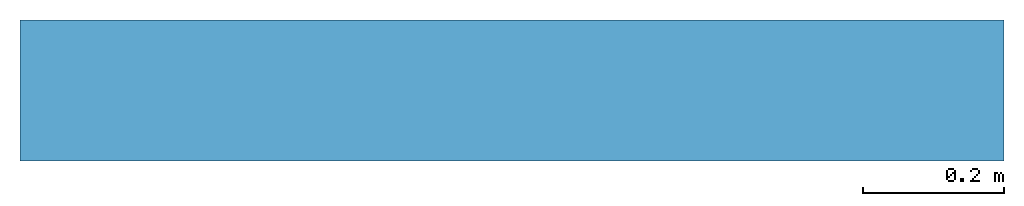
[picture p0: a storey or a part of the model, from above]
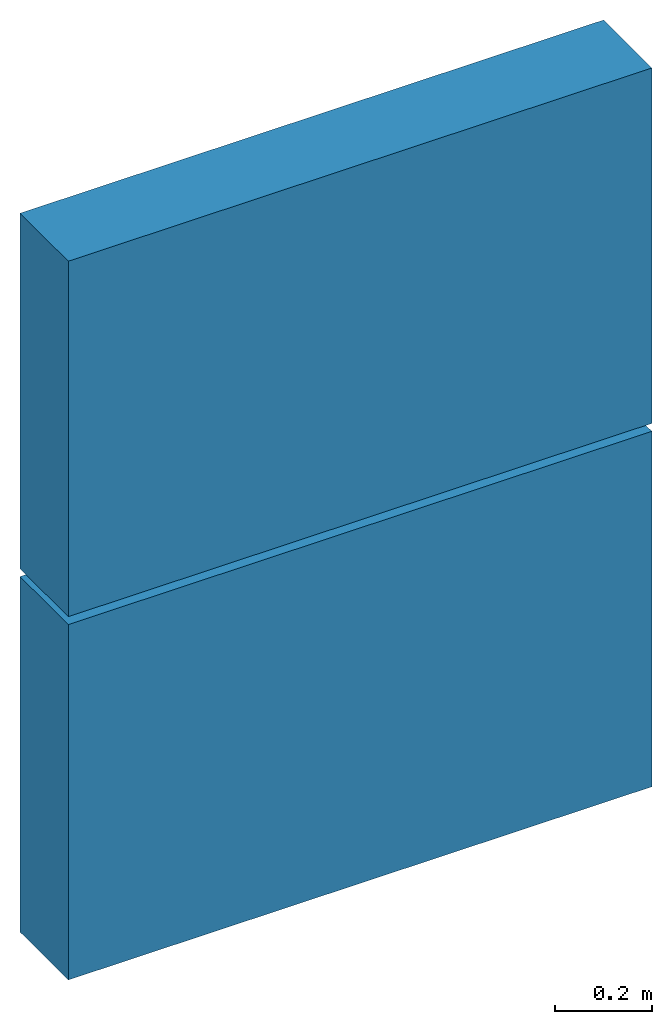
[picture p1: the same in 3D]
Properties of the parts of a building model (IFC2X3), part 1 of 2

# File
Description: ViewDefinition [CoordinationView_V2.0]
File name: Project Number
Time: 2020-09-23T15:33:14
Written by: The EXPRESS Data Manager Version 5.02.0100.07 : 28 Aug 2013
Made in: 21.0.0.383 - Exporter 21.0.0.383 - Alternate UI 21.0.0.383
Comment: STEP Physical File produced by: The EXPRESS Data Manager Version 5.02.0100.07 : 28 Aug 2013 * Module: EDMstepFileFactory/EDMstandAlone * Creation date: Wed Sep 23 15:33:14 2020 * Host: DESKTOP-DG8BND5 * Database: C:\Users\X\AppData\Local\Temp\6b4c7af7-08d6-41d8-b2e5-88945e1ad714\b9ea3a23-58ec-455c-9557-a9c1af2dff10\ifc * Database version: 5507 * Database creation date: Wed Sep 23 15:31:38 2020 * Schema: IFC2X3 * Model: DataRepository.ifc * Model creation date: Wed Sep 23 15:31:39 2020 * Header model: DataRepository.ifc_HeaderModel * Header model creation date: Wed Sep 23 15:31:39 2020 * EDMuser: sdai-user * EDMgroup: sdai-group * License ID and type: 5605 : Permanent license. Expiry date: * EDMstepFileFactory options: 020000

# IfcProject, Project Number
LongName: Project Name; Phase: Project Status

# IfcSite, Default
RefLatitude: 48, 41, 46, 352233; RefLongitude: 6, 11, 34, 519615; RefElevation: 0 mm
Pset_ProductRequirements - Category: Project Information
Other - Category: Project Information; Client Name: Owner; Project Address: Enter address here; Project Issue Date: Issue Date; Project Name: Project Name; Project Number: Project Number; Project Status: Project Status

# IfcBuilding
Pset_BuildingCommon - NumberOfStoreys: 5
Pset_ProductRequirements - Category: Project Information
Other - Category: Project Information; Client Name: Owner; Project Address: Enter address here; Project Issue Date: Issue Date; Project Name: Project Name; Project Number: Project Number; Project Status: Project Status

# IfcBuildingStorey: Level:Circle Head - Project Datum (5)
Other(Type) - Category: Levels; Family Name: Level
Identity Data(Type) - Type Name: Circle Head - Project Datum
Graphics(Type) - Color: 0; Line Pattern: Centre; Line Weight: 1; Symbol: Anno_Level_Head_Circle: Standard; Symbol at End 1 Default: yes; Symbol at End 2 Default: no
Constraints(Type) - Elevation Base: Project Base Point
Pset_ProductRequirements - Category: Levels
Dimensions - Computation Height: 0 mm
Identity Data - Building Story: yes
Other - Category: Levels; Family: Level: Circle Head - Project Datum; Family and Type: Level: Circle Head - Project Datum; Type: Level: Circle Head - Project Datum; Type Id: Level: Circle Head - Project Datum
Name | LongName = Pset_AirSideSystemInformation, Name = Pset_ProductRequirements, Name = Identity Data, Name | Elevation (mm) = Constraints, Elevation (mm) | Structural
R-1 | R-1 | -3500 | yes
RDC | RDC | 0 | no
R+1 | R+1 | 3660 | no
R+2 | R+2 | 7320 | no
TOITURE | TOITURE | 10840 | yes

# IfcBeam: M_Concrete-Rectangular Beam:200x300 mm, M_Concrete-Rectangular Beam:200x300 mm:497822
In: R-1
Type - Dimensions - b: 200 mm; h: 300 mm
Type - Identity Data - OmniClass Number: 23.25.30.11.14.14; OmniClass Title: Beams; Type Name: 200x300 mm
Type - Other - Category: Structural Framing; Family Name: M_Concrete-Rectangular Beam
Type - Structural - Section Shape: 0
Type - Pset_BeamCommon - IsExternal: no; LoadBearing: yes; Reference: 200x300 mm
Type - Pset_ProductRequirements - Category: Structural Framing
Type - Pset_QuantityTakeOff - Reference: 200x300 mm
Type - Pset_ReinforcementBarPitchOfBeam - Reference: 200x300 mm
Material: Concrete, Cast-in-Place gray
Pset_BeamCommon - Slope: 0 deg; Span: 1739.96 mm
Pset_QuantityTakeOff - sets with these values: 2
Constraints - Cross-Section Rotation: 0 deg; End Level Offset: 2330 mm; Reference Level: Level: R-1; Reference Level Elevation: -3500 mm; Start Level Offset: 2330 mm
Dimensions - Elevation at Bottom: -1470 mm; Elevation at Top: -1170 mm; Length: 1739.96 mm; Volume: 0.0989977 m3
Geometric Position - Join Status: Both joins enabled; y Justification: Origin; y Offset Value: 0 mm; yz Justification: Uniform; z Justification: Top; z Offset Value: 0 mm
Materials and Finishes - Structural Material: Concrete, Cast-in-Place gray
Other - Family: M_Concrete-Rectangular Beam: 200x300 mm; Family and Type: M_Concrete-Rectangular Beam: 200x300 mm; Type: M_Concrete-Rectangular Beam: 200x300 mm; Type Id: M_Concrete-Rectangular Beam: 200x300 mm
Phasing - Phase Created: New Construction
Structural - Enable Analytical Model: yes; Rebar Cover - Bottom Face: Rebar Cover Settings: Rebar Cover 1; Rebar Cover - Other Faces: Rebar Cover Settings: Rebar Cover 1; Rebar Cover - Top Face: Rebar Cover Settings: Rebar Cover 1; Cut Length: 1649.96 mm; Structural Usage: Secondary

# IfcBeam: NBS_AndertonConcreteProductsLtd_PrcstConcPnls_BallastBoard300:PPT TYPE4 (42)
Type - Constraints - Default Elevation: 0 mm
Type - Data - EdgeDetails: Plain; EnvironmentalProductDeclaration: n/a; Weight: 60 kg
Type - Dimensions - Height: 898.3 mm; Length: 8120 mm; Width: 200 mm
Type - General - Author: NBS; BIMObjectName: NBS_AndertonConcreteProductsLtd_PrecastConcretePanels_BallastBoard300; ManufacturerName: Anderton Concrete Products Ltd; NBSDescription: Precast concrete paels; Revision: n/a; Uniclass2015Code: Pr_20_93_71_17; Uniclass2015Title: Concrete panels; Uniclass2015Version: Products v1.5; Version: 4
Type - Identity Data - Type Name: PPT TYPE4
Type - Materials and Finishes - PanelMaterial: Concrete, Precast Smooth, Light Grey
Type - Other - Category: Generic Models; AccessibilityPerformance: n/a; AssetType: Fixed; CodePerformance: n/a; Color: n/a; Constituents: n/a; DurationUnit: year; ExpectedLife: n/a; Family Name: NBS_AndertonConcreteProductsLtd_PrcstConcPnls_BallastBoard300; Features: Quick and easy to install, contains steel reinforcement, Network Rail approved; Finish: n/a; Grade: n/a; Material: Concrete; ModelNumber: n/a; ModelReference: Ballast Board; Name: PrecastConcretePanels_BallastBoard300_AndertonConcreteProductsLtd; NominalHeight: 2910 mm; NominalLength: 10337 mm; NominalWidth: 200 mm; ReplacementCost: n/a; Shape: Rectangular; Size: 1830 x 300 x 50 mm; SustainabilityPerformance: n/a; WarrantyDescription: n/a; WarrantyDurationLabor: n/a; WarrantyDurationParts: n/a; WarrantyDurationUnit: year; WarrantyGuarantorLabor: n/a; WarrantyGuarantorParts: n/a
Type - Pset_BeamCommon - LoadBearing: yes; Reference: n/a; Slope: 0 deg; IsExternal: yes; Span: 1830 mm; FireRating: n/a
Type - Pset_ConcreteElementGeneral - EnvironmentalClass: n/a; FireRating: n/a; LifeCycleEnvironmentalLoad: n/a; DimensionalAccuracyClass: n/a; ConstructionToleranceClass: n/a; ConstructionType: n/a
Type - Pset_ElementShading - Color: n/a
Type - Pset_ManufacturerTypeInformation - ModelReference: Ballast Board
Type - Pset_ProductRequirements - Name: PrecastConcretePanels_BallastBoard300_AndertonConcreteProductsLtd; Category: Generic Models
Type - Pset_QuantityTakeOff - Reference: n/a
Type - Pset_ReinforcementBarPitchOfBeam - Reference: n/a
Material: Concrete, Precast Smooth, Light Grey
Pset_ManufacturerOccurrence - BarCode: n/a; SerialNumber: n/a
Pset_PrecastConcreteElementGeneral - SerialNumber: n/a
Pset_QuantityTakeOff - sets with these values: 2
Constraints - Moves With Nearby Elements: no
Dimensions - Area: 9.09786 m2; Volume: 1.45884 m3
Other - AssetIdentifier: n/a; BarCode: n/a; Family: NBS_AndertonConcreteProductsLtd_PrcstConcPnls_BallastBoard300: PPT TYPE4; Family and Type: NBS_AndertonConcreteProductsLtd_PrcstConcPnls_BallastBoard300: PPT TYPE4; InstallationDate: 1900-12-31T23:59:59; SerialNumber: n/a; TagNumber: n/a; Type: NBS_AndertonConcreteProductsLtd_PrcstConcPnls_BallastBoard300: PPT TYPE4; Type Id: NBS_AndertonConcreteProductsLtd_PrcstConcPnls_BallastBoard300: PPT TYPE4; WarrantyStartDate: 1900-12-31T23:59:59
Structural - Rebar Cover: Rebar Cover Settings: Rebar Cover 1
Name (NBS_AndertonConcreteProductsLtd_PrcstConcPnls_BallastBoard300:PPT TYPE4:...) | In | Level | Elevation from Level (mm) = Offset from Host (mm) | Host | Comments | Phase Created
424100 | RDC | Level: RDC | 2010 | Level : RDC | ThisIsNew | New Construction
424610 | RDC | Level: RDC | 1091.7 | Level : RDC | ThisIsNew | New Construction
424641 | RDC | Level: RDC | 173.4 | Level : RDC | ThisIsNew | New Construction
424680 | RDC | Level: RDC | 2928.3 | Level : RDC | ThisIsNew | New Construction
424690 | R+1 | Level: R+1 | 186.6 | Level : R+1 | ThisIsNew | New Construction
424729 | R+1 | Level: R+1 | 1104.9 | Level : R+1 | ThisIsNew | New Construction
424743 | R+1 | Level: R+1 | 2023.2 | Level : R+1 | ThisIsNew | New Construction
424763 | R+1 | Level: R+1 | 2941.5 | Level : R+1 | ThisIsNew | New Construction
424773 | R+2 | Level: R+2 | 199.8 | Level : R+2 | ThisIsNew | New Construction
430433 | RDC | Level: RDC | 2928.3 | Level : RDC | ThisIsExisting | Existing
430434 | R+1 | Level: R+1 | 186.6 | Level : R+1 | ThisIsExisting | Existing
430435 | R+1 | Level: R+1 | 1104.9 | Level : R+1 | ThisIsExisting | Existing
430436 | R+1 | Level: R+1 | 2023.2 | Level : R+1 | ThisIsExisting | Existing
430437 | R+1 | Level: R+1 | 2941.5 | Level : R+1 | ThisIsExisting | Existing
430438 | R+2 | Level: R+2 | 199.8 | Level : R+2 | ThisIsExisting | Existing
585489 | R+2 | Level: R+2 | 1118.1 | Level : R+2 | ThisIsExisting | Existing
585513 | R+2 | Level: R+2 | 2036.4 | Level : R+2 | ThisIsExisting | Existing
585540 | R+2 | Level: R+2 | 2954.7 | Level : R+2 | ThisIsExisting | Existing
585692 | RDC | Level: RDC | 2010 | Level : RDC | ThisIsExisting | Existing
585693 | RDC | Level: RDC | 1091.7 | Level : RDC | ThisIsExisting | Existing
585694 | RDC | Level: RDC | 173.4 | Level : RDC | ThisIsExisting | Existing
585695 | RDC | Level: RDC | 2928.3 | Level : RDC | ThisIsExisting | Existing
585696 | R+1 | Level: R+1 | 186.6 | Level : R+1 | ThisIsExisting | Existing
585697 | R+1 | Level: R+1 | 1104.9 | Level : R+1 | ThisIsExisting | Existing
585698 | R+1 | Level: R+1 | 2023.2 | Level : R+1 | ThisIsExisting | Existing
585699 | R+1 | Level: R+1 | 2941.5 | Level : R+1 | ThisIsExisting | Existing
585700 | R+2 | Level: R+2 | 199.8 | Level : R+2 | ThisIsExisting | Existing
585701 | RDC | Level: RDC | 2928.3 | Level : RDC | ThisIsExisting | Existing
585702 | R+1 | Level: R+1 | 186.6 | Level : R+1 | ThisIsExisting | Existing
585703 | R+1 | Level: R+1 | 1104.9 | Level : R+1 | ThisIsExisting | Existing
585704 | R+1 | Level: R+1 | 2023.2 | Level : R+1 | ThisIsExisting | Existing
585705 | R+1 | Level: R+1 | 2941.5 | Level : R+1 | ThisIsExisting | Existing
585706 | R+2 | Level: R+2 | 199.8 | Level : R+2 | ThisIsExisting | Existing
585707 | R+2 | Level: R+2 | 1118.1 | Level : R+2 | ThisIsExisting | Existing
585708 | R+2 | Level: R+2 | 2036.4 | Level : R+2 | ThisIsExisting | Existing
585709 | R+2 | Level: R+2 | 2954.7 | Level : R+2 | ThisIsExisting | Existing
585859 | R+2 | Level: R+2 | 1118.1 | Level : R+2 | ThisIsExisting | Existing
585870 | R+2 | Level: R+2 | 2036.4 | Level : R+2 | ThisIsExisting | Existing
586358 | R+2 | Level: R+2 | 1118.1 | Level : R+2 | ThisIsNew | New Construction
586370 | R+2 | Level: R+2 | 2036.4 | Level : R+2 | ThisIsNew | New Construction
586384 | R+2 | Level: R+2 | 2954.7 | Level : R+2 | ThisIsNew | New Construction
586434 | R+2 | Level: R+2 | 2954.7 | Level : R+2 | ThisIsExisting | Existing

# IfcBeam: NBS_AndertonConcreteProductsLtd_PrcstConcPnls_BallastBoard300:PPT TYPE5 (42)
Type - Constraints - Default Elevation: 0 mm
Type - Data - EdgeDetails: Plain; EnvironmentalProductDeclaration: n/a; Weight: 60 kg
Type - Dimensions - Height: 898.3 mm; Length: 1525 mm; Width: 200 mm
Type - General - Author: NBS; BIMObjectName: NBS_AndertonConcreteProductsLtd_PrecastConcretePanels_BallastBoard300; ManufacturerName: Anderton Concrete Products Ltd; NBSDescription: Precast concrete paels; Revision: n/a; Uniclass2015Code: Pr_20_93_71_17; Uniclass2015Title: Concrete panels; Uniclass2015Version: Products v1.5; Version: 4
Type - Identity Data - Type Name: PPT TYPE5
Type - Materials and Finishes - PanelMaterial: Concrete, Precast Smooth, Light Grey
Type - Other - Category: Generic Models; AccessibilityPerformance: n/a; AssetType: Fixed; CodePerformance: n/a; Color: n/a; Constituents: n/a; DurationUnit: year; ExpectedLife: n/a; Family Name: NBS_AndertonConcreteProductsLtd_PrcstConcPnls_BallastBoard300; Features: Quick and easy to install, contains steel reinforcement, Network Rail approved; Finish: n/a; Grade: n/a; Material: Concrete; ModelNumber: n/a; ModelReference: Ballast Board; Name: PrecastConcretePanels_BallastBoard300_AndertonConcreteProductsLtd; NominalHeight: 2910 mm; NominalLength: 10337 mm; NominalWidth: 200 mm; ReplacementCost: n/a; Shape: Rectangular; Size: 1830 x 300 x 50 mm; SustainabilityPerformance: n/a; WarrantyDescription: n/a; WarrantyDurationLabor: n/a; WarrantyDurationParts: n/a; WarrantyDurationUnit: year; WarrantyGuarantorLabor: n/a; WarrantyGuarantorParts: n/a
Type - Pset_BeamCommon - LoadBearing: yes; Reference: n/a; Slope: 0 deg; IsExternal: yes; Span: 1830 mm; FireRating: n/a
Type - Pset_ConcreteElementGeneral - EnvironmentalClass: n/a; FireRating: n/a; LifeCycleEnvironmentalLoad: n/a; DimensionalAccuracyClass: n/a; ConstructionToleranceClass: n/a; ConstructionType: n/a
Type - Pset_ElementShading - Color: n/a
Type - Pset_ManufacturerTypeInformation - ModelReference: Ballast Board
Type - Pset_ProductRequirements - Name: PrecastConcretePanels_BallastBoard300_AndertonConcreteProductsLtd; Category: Generic Models
Type - Pset_QuantityTakeOff - Reference: n/a
Type - Pset_ReinforcementBarPitchOfBeam - Reference: n/a
Material: Concrete, Precast Smooth, Light Grey
Pset_ManufacturerOccurrence - BarCode: n/a; SerialNumber: n/a
Pset_PrecastConcreteElementGeneral - SerialNumber: n/a
Pset_QuantityTakeOff - sets with these values: 2
Constraints - Moves With Nearby Elements: no
Dimensions - Area: 1.85457 m2; Volume: 0.273982 m3
Identity Data - Comments: ThisIsExisting
Other - AssetIdentifier: n/a; BarCode: n/a; Family: NBS_AndertonConcreteProductsLtd_PrcstConcPnls_BallastBoard300: PPT TYPE5; Family and Type: NBS_AndertonConcreteProductsLtd_PrcstConcPnls_BallastBoard300: PPT TYPE5; InstallationDate: 1900-12-31T23:59:59; SerialNumber: n/a; TagNumber: n/a; Type: NBS_AndertonConcreteProductsLtd_PrcstConcPnls_BallastBoard300: PPT TYPE5; Type Id: NBS_AndertonConcreteProductsLtd_PrcstConcPnls_BallastBoard300: PPT TYPE5; WarrantyStartDate: 1900-12-31T23:59:59
Phasing - Phase Created: Existing
Structural - Rebar Cover: Rebar Cover Settings: Rebar Cover 1
Name (NBS_AndertonConcreteProductsLtd_PrcstConcPnls_BallastBoard300:PPT TYPE5:...) | In | Level | Elevation from Level (mm) = Offset from Host (mm) | Host
424916 | RDC | Level: RDC | 2010 | Level : RDC
424917 | RDC | Level: RDC | 1091.7 | Level : RDC
424918 | RDC | Level: RDC | 173.4 | Level : RDC
424919 | RDC | Level: RDC | 2928.3 | Level : RDC
424923 | R+1 | Level: R+1 | 2941.5 | Level : R+1
424924 | R+2 | Level: R+2 | 199.8 | Level : R+2
428777 | RDC | Level: RDC | 2010 | Level : RDC
428778 | RDC | Level: RDC | 1091.7 | Level : RDC
428779 | RDC | Level: RDC | 173.4 | Level : RDC
428780 | RDC | Level: RDC | 2928.3 | Level : RDC
428784 | R+1 | Level: R+1 | 2941.5 | Level : R+1
428785 | R+2 | Level: R+2 | 199.8 | Level : R+2
585485 | R+2 | Level: R+2 | 1118.1 | Level : R+2
585487 | R+2 | Level: R+2 | 1118.1 | Level : R+2
585509 | R+2 | Level: R+2 | 2036.4 | Level : R+2
585511 | R+2 | Level: R+2 | 2036.4 | Level : R+2
585536 | R+2 | Level: R+2 | 2954.7 | Level : R+2
585538 | R+2 | Level: R+2 | 2954.7 | Level : R+2
585606 | RDC | Level: RDC | 2010 | Level : RDC
585607 | RDC | Level: RDC | 1091.7 | Level : RDC
585608 | RDC | Level: RDC | 173.4 | Level : RDC
585609 | RDC | Level: RDC | 2928.3 | Level : RDC
585610 | R+1 | Level: R+1 | 186.6 | Level : R+1
585611 | R+1 | Level: R+1 | 1104.9 | Level : R+1
585612 | R+1 | Level: R+1 | 2023.2 | Level : R+1
585613 | R+1 | Level: R+1 | 2941.5 | Level : R+1
585614 | R+2 | Level: R+2 | 199.8 | Level : R+2
585615 | RDC | Level: RDC | 2010 | Level : RDC
585616 | RDC | Level: RDC | 1091.7 | Level : RDC
585617 | RDC | Level: RDC | 173.4 | Level : RDC
585618 | RDC | Level: RDC | 2928.3 | Level : RDC
585619 | R+1 | Level: R+1 | 186.6 | Level : R+1
585620 | R+1 | Level: R+1 | 1104.9 | Level : R+1
585621 | R+1 | Level: R+1 | 2023.2 | Level : R+1
585622 | R+1 | Level: R+1 | 2941.5 | Level : R+1
585623 | R+2 | Level: R+2 | 199.8 | Level : R+2
585624 | R+2 | Level: R+2 | 1118.1 | Level : R+2
585625 | R+2 | Level: R+2 | 1118.1 | Level : R+2
585626 | R+2 | Level: R+2 | 2036.4 | Level : R+2
585627 | R+2 | Level: R+2 | 2036.4 | Level : R+2
585628 | R+2 | Level: R+2 | 2954.7 | Level : R+2
585629 | R+2 | Level: R+2 | 2954.7 | Level : R+2

# IfcBeam: NBS_AndertonConcreteProductsLtd_PrcstConcPnls_BallastBoard300:PPT TYPE6 (18)
Type - Constraints - Default Elevation: 0 mm
Type - Data - EdgeDetails: Plain; EnvironmentalProductDeclaration: n/a; Weight: 60 kg
Type - Dimensions - Height: 898.3 mm; Length: 6066.3 mm; Width: 200 mm
Type - General - Author: NBS; BIMObjectName: NBS_AndertonConcreteProductsLtd_PrecastConcretePanels_BallastBoard300; ManufacturerName: Anderton Concrete Products Ltd; NBSDescription: Precast concrete paels; Revision: n/a; Uniclass2015Code: Pr_20_93_71_17; Uniclass2015Title: Concrete panels; Uniclass2015Version: Products v1.5; Version: 4
Type - Identity Data - Type Name: PPT TYPE6
Type - Materials and Finishes - PanelMaterial: Concrete, Precast Smooth, Light Grey
Type - Other - Category: Generic Models; AccessibilityPerformance: n/a; AssetType: Fixed; CodePerformance: n/a; Color: n/a; Constituents: n/a; DurationUnit: year; ExpectedLife: n/a; Family Name: NBS_AndertonConcreteProductsLtd_PrcstConcPnls_BallastBoard300; Features: Quick and easy to install, contains steel reinforcement, Network Rail approved; Finish: n/a; Grade: n/a; Material: Concrete; ModelNumber: n/a; ModelReference: Ballast Board; Name: PrecastConcretePanels_BallastBoard300_AndertonConcreteProductsLtd; NominalHeight: 2910 mm; NominalLength: 10337 mm; NominalWidth: 200 mm; ReplacementCost: n/a; Shape: Rectangular; Size: 1830 x 300 x 50 mm; SustainabilityPerformance: n/a; WarrantyDescription: n/a; WarrantyDurationLabor: n/a; WarrantyDurationParts: n/a; WarrantyDurationUnit: year; WarrantyGuarantorLabor: n/a; WarrantyGuarantorParts: n/a
Type - Pset_BeamCommon - LoadBearing: yes; Reference: n/a; Slope: 0 deg; IsExternal: yes; Span: 1830 mm; FireRating: n/a
Type - Pset_ConcreteElementGeneral - EnvironmentalClass: n/a; FireRating: n/a; LifeCycleEnvironmentalLoad: n/a; DimensionalAccuracyClass: n/a; ConstructionToleranceClass: n/a; ConstructionType: n/a
Type - Pset_ElementShading - Color: n/a
Type - Pset_ManufacturerTypeInformation - ModelReference: Ballast Board
Type - Pset_ProductRequirements - Name: PrecastConcretePanels_BallastBoard300_AndertonConcreteProductsLtd; Category: Generic Models
Type - Pset_QuantityTakeOff - Reference: n/a
Type - Pset_ReinforcementBarPitchOfBeam - Reference: n/a
Material: Concrete, Precast Smooth, Light Grey
Pset_ManufacturerOccurrence - BarCode: n/a; SerialNumber: n/a
Pset_PrecastConcreteElementGeneral - SerialNumber: n/a
Pset_QuantityTakeOff - sets with these values: 2
Constraints - Moves With Nearby Elements: no
Dimensions - Area: 6.84228 m2; Volume: 1.08987 m3
Identity Data - Comments: ThisIsExisting
Other - AssetIdentifier: n/a; BarCode: n/a; Family: NBS_AndertonConcreteProductsLtd_PrcstConcPnls_BallastBoard300: PPT TYPE6; Family and Type: NBS_AndertonConcreteProductsLtd_PrcstConcPnls_BallastBoard300: PPT TYPE6; InstallationDate: 1900-12-31T23:59:59; SerialNumber: n/a; TagNumber: n/a; Type: NBS_AndertonConcreteProductsLtd_PrcstConcPnls_BallastBoard300: PPT TYPE6; Type Id: NBS_AndertonConcreteProductsLtd_PrcstConcPnls_BallastBoard300: PPT TYPE6; WarrantyStartDate: 1900-12-31T23:59:59
Phasing - Phase Created: Existing
Structural - Rebar Cover: Rebar Cover Settings: Rebar Cover 1
Name (NBS_AndertonConcreteProductsLtd_PrcstConcPnls_BallastBoard300:PPT TYPE6:...) | In | Level | Elevation from Level (mm) = Offset from Host (mm) | Host
426953 | RDC | Level: RDC | 2928.3 | Level : RDC
426954 | R+1 | Level: R+1 | 186.6 | Level : R+1
426955 | R+1 | Level: R+1 | 1104.9 | Level : R+1
426956 | R+1 | Level: R+1 | 2023.2 | Level : R+1
426957 | R+1 | Level: R+1 | 2941.5 | Level : R+1
426958 | R+2 | Level: R+2 | 199.8 | Level : R+2
585486 | R+2 | Level: R+2 | 1118.1 | Level : R+2
585510 | R+2 | Level: R+2 | 2036.4 | Level : R+2
585537 | R+2 | Level: R+2 | 2954.7 | Level : R+2
585577 | RDC | Level: RDC | 2928.3 | Level : RDC
585578 | R+1 | Level: R+1 | 186.6 | Level : R+1
585579 | R+1 | Level: R+1 | 1104.9 | Level : R+1
585580 | R+1 | Level: R+1 | 2023.2 | Level : R+1
585581 | R+1 | Level: R+1 | 2941.5 | Level : R+1
585582 | R+2 | Level: R+2 | 199.8 | Level : R+2
585583 | R+2 | Level: R+2 | 1118.1 | Level : R+2
585584 | R+2 | Level: R+2 | 2036.4 | Level : R+2
585585 | R+2 | Level: R+2 | 2954.7 | Level : R+2

# IfcBeam: NBS_AndertonConcreteProductsLtd_PrcstConcPnls_BallastBoard300:PPT TYPE7 (86)
Type - Constraints - Default Elevation: 0 mm
Type - Data - EdgeDetails: Plain; EnvironmentalProductDeclaration: n/a; Weight: 60 kg
Type - Dimensions - Height: 898.3 mm; Length: 1395 mm; Width: 200 mm
Type - General - Author: NBS; BIMObjectName: NBS_AndertonConcreteProductsLtd_PrecastConcretePanels_BallastBoard300; ManufacturerName: Anderton Concrete Products Ltd; NBSDescription: Precast concrete paels; Revision: n/a; Uniclass2015Code: Pr_20_93_71_17; Uniclass2015Title: Concrete panels; Uniclass2015Version: Products v1.5; Version: 4
Type - Identity Data - Type Name: PPT TYPE7
Type - Materials and Finishes - PanelMaterial: Concrete, Precast Smooth, Light Grey
Type - Other - Category: Generic Models; AccessibilityPerformance: n/a; AssetType: Fixed; CodePerformance: n/a; Color: n/a; Constituents: n/a; DurationUnit: year; ExpectedLife: n/a; Family Name: NBS_AndertonConcreteProductsLtd_PrcstConcPnls_BallastBoard300; Features: Quick and easy to install, contains steel reinforcement, Network Rail approved; Finish: n/a; Grade: n/a; Material: Concrete; ModelNumber: n/a; ModelReference: Ballast Board; Name: PrecastConcretePanels_BallastBoard300_AndertonConcreteProductsLtd; NominalHeight: 2910 mm; NominalLength: 10337 mm; NominalWidth: 200 mm; ReplacementCost: n/a; Shape: Rectangular; Size: 1830 x 300 x 50 mm; SustainabilityPerformance: n/a; WarrantyDescription: n/a; WarrantyDurationLabor: n/a; WarrantyDurationParts: n/a; WarrantyDurationUnit: year; WarrantyGuarantorLabor: n/a; WarrantyGuarantorParts: n/a
Type - Pset_BeamCommon - LoadBearing: yes; Reference: n/a; Slope: 0 deg; IsExternal: yes; Span: 1830 mm; FireRating: n/a
Type - Pset_ConcreteElementGeneral - EnvironmentalClass: n/a; FireRating: n/a; LifeCycleEnvironmentalLoad: n/a; DimensionalAccuracyClass: n/a; ConstructionToleranceClass: n/a; ConstructionType: n/a
Type - Pset_ElementShading - Color: n/a
Type - Pset_ManufacturerTypeInformation - ModelReference: Ballast Board
Type - Pset_ProductRequirements - Name: PrecastConcretePanels_BallastBoard300_AndertonConcreteProductsLtd; Category: Generic Models
Type - Pset_QuantityTakeOff - Reference: n/a
Type - Pset_ReinforcementBarPitchOfBeam - Reference: n/a
Material: Concrete, Precast Smooth, Light Grey
Pset_ManufacturerOccurrence - BarCode: n/a; SerialNumber: n/a
Pset_PrecastConcreteElementGeneral - SerialNumber: n/a
Pset_QuantityTakeOff - sets with these values: 2
Constraints - Moves With Nearby Elements: no
Dimensions - Area: 1.71179 m2; Volume: 0.250626 m3
Other - AssetIdentifier: n/a; BarCode: n/a; Family: NBS_AndertonConcreteProductsLtd_PrcstConcPnls_BallastBoard300: PPT TYPE7; Family and Type: NBS_AndertonConcreteProductsLtd_PrcstConcPnls_BallastBoard300: PPT TYPE7; InstallationDate: 1900-12-31T23:59:59; SerialNumber: n/a; TagNumber: n/a; Type: NBS_AndertonConcreteProductsLtd_PrcstConcPnls_BallastBoard300: PPT TYPE7; Type Id: NBS_AndertonConcreteProductsLtd_PrcstConcPnls_BallastBoard300: PPT TYPE7; WarrantyStartDate: 1900-12-31T23:59:59
Structural - Rebar Cover: Rebar Cover Settings: Rebar Cover 1
Name (NBS_AndertonConcreteProductsLtd_PrcstConcPnls_BallastBoard300:PPT TYPE7:...) | In | Level | Elevation from Level (mm) = Offset from Host (mm) | Host | Comments | Phase Created
428813 | RDC | Level: RDC | 2010 | Level : RDC | ThisIsExisting | Existing
428814 | RDC | Level: RDC | 1091.7 | Level : RDC | ThisIsExisting | Existing
428815 | RDC | Level: RDC | 173.4 | Level : RDC | ThisIsExisting | Existing
428816 | RDC | Level: RDC | 2928.3 | Level : RDC | ThisIsExisting | Existing
428817 | R+1 | Level: R+1 | 186.6 | Level : R+1 | ThisIsExisting | Existing
428818 | R+1 | Level: R+1 | 1104.9 | Level : R+1 | ThisIsExisting | Existing
428819 | R+1 | Level: R+1 | 2023.2 | Level : R+1 | ThisIsExisting | Existing
428820 | R+1 | Level: R+1 | 2941.5 | Level : R+1 | ThisIsExisting | Existing
428821 | R+2 | Level: R+2 | 199.8 | Level : R+2 | ThisIsExisting | Existing
428895 | RDC | Level: RDC | 173.4 | Level : RDC | ThisIsExisting | Existing
428984 | RDC | Level: RDC | 2010 | Level : RDC | ThisIsExisting | Existing
428985 | RDC | Level: RDC | 1091.7 | Level : RDC | ThisIsExisting | Existing
428986 | RDC | Level: RDC | 2928.3 | Level : RDC | ThisIsExisting | Existing
428987 | R+1 | Level: R+1 | 186.6 | Level : R+1 | ThisIsExisting | Existing
428988 | R+1 | Level: R+1 | 1104.9 | Level : R+1 | ThisIsExisting | Existing
428989 | R+1 | Level: R+1 | 2023.2 | Level : R+1 | ThisIsExisting | Existing
428990 | R+1 | Level: R+1 | 2941.5 | Level : R+1 | ThisIsExisting | Existing
430464 | RDC | Level: RDC | 2928.3 | Level : RDC | ThisIsExisting | Existing
430465 | R+1 | Level: R+1 | 186.6 | Level : R+1 | ThisIsExisting | Existing
430466 | R+1 | Level: R+1 | 1104.9 | Level : R+1 | ThisIsExisting | Existing
430467 | R+1 | Level: R+1 | 2023.2 | Level : R+1 | ThisIsExisting | Existing
430468 | R+1 | Level: R+1 | 2941.5 | Level : R+1 | ThisIsExisting | Existing
500897 | R+1 | Level: R+1 | 2023.2 | Level : R+1 | ThisIsNew | New Construction
501332 | R+1 | Level: R+1 | 2941.5 | Level : R+1 | ThisIsNew | New Construction
501372 | R+1 | Level: R+1 | 1104.9 | Level : R+1 | ThisIsNew | New Construction
501373 | R+1 | Level: R+1 | 186.6 | Level : R+1 | ThisIsNew | New Construction
501413 | R+2 | Level: R+2 | 199.8 | Level : R+2 | ThisIsNew | New Construction
501535 | RDC | Level: RDC | 173.4 | Level : RDC | ThisIsNew | New Construction
501753 | RDC | Level: RDC | 1091.7 | Level : RDC | ThisIsNew | New Construction
501808 | RDC | Level: RDC | 2010 | Level : RDC | ThisIsNew | New Construction
501821 | RDC | Level: RDC | 2928.3 | Level : RDC | ThisIsNew | New Construction
585441 | R+1 | Level: R+1 | 3859.8 | Level : R+1 | ThisIsExisting | Existing
585488 | R+2 | Level: R+2 | 1118.1 | Level : R+2 | ThisIsExisting | Existing
585490 | R+1 | Level: R+1 | 4778.1 | Level : R+1 | ThisIsExisting | Existing
585512 | R+2 | Level: R+2 | 2036.4 | Level : R+2 | ThisIsExisting | Existing
585514 | R+1 | Level: R+1 | 5696.4 | Level : R+1 | ThisIsExisting | Existing
585539 | R+2 | Level: R+2 | 2954.7 | Level : R+2 | ThisIsExisting | Existing
585541 | R+1 | Level: R+1 | 6614.7 | Level : R+1 | ThisIsExisting | Existing
585642 | RDC | Level: RDC | 2010 | Level : RDC | ThisIsExisting | Existing
585643 | RDC | Level: RDC | 1091.7 | Level : RDC | ThisIsExisting | Existing
585644 | RDC | Level: RDC | 173.4 | Level : RDC | ThisIsExisting | Existing
585645 | RDC | Level: RDC | 2928.3 | Level : RDC | ThisIsExisting | Existing
585646 | R+1 | Level: R+1 | 186.6 | Level : R+1 | ThisIsExisting | Existing
585647 | R+1 | Level: R+1 | 1104.9 | Level : R+1 | ThisIsExisting | Existing
585648 | R+1 | Level: R+1 | 2023.2 | Level : R+1 | ThisIsExisting | Existing
585649 | R+1 | Level: R+1 | 2941.5 | Level : R+1 | ThisIsExisting | Existing
585650 | R+2 | Level: R+2 | 199.8 | Level : R+2 | ThisIsExisting | Existing
585651 | RDC | Level: RDC | 173.4 | Level : RDC | ThisIsExisting | Existing
585652 | RDC | Level: RDC | 2010 | Level : RDC | ThisIsExisting | Existing
585653 | RDC | Level: RDC | 1091.7 | Level : RDC | ThisIsExisting | Existing
585654 | RDC | Level: RDC | 2928.3 | Level : RDC | ThisIsExisting | Existing
585655 | R+1 | Level: R+1 | 186.6 | Level : R+1 | ThisIsExisting | Existing
585656 | R+1 | Level: R+1 | 1104.9 | Level : R+1 | ThisIsExisting | Existing
585657 | R+1 | Level: R+1 | 2023.2 | Level : R+1 | ThisIsExisting | Existing
585658 | R+1 | Level: R+1 | 2941.5 | Level : R+1 | ThisIsExisting | Existing
585659 | RDC | Level: RDC | 2928.3 | Level : RDC | ThisIsExisting | Existing
585660 | R+1 | Level: R+1 | 186.6 | Level : R+1 | ThisIsExisting | Existing
585661 | R+1 | Level: R+1 | 1104.9 | Level : R+1 | ThisIsExisting | Existing
585662 | R+1 | Level: R+1 | 2023.2 | Level : R+1 | ThisIsExisting | Existing
585663 | R+1 | Level: R+1 | 2941.5 | Level : R+1 | ThisIsExisting | Existing
585664 | R+1 | Level: R+1 | 2023.2 | Level : R+1 | ThisIsExisting | Existing
585665 | R+1 | Level: R+1 | 2941.5 | Level : R+1 | ThisIsExisting | Existing
585666 | R+1 | Level: R+1 | 1104.9 | Level : R+1 | ThisIsExisting | Existing
585667 | R+1 | Level: R+1 | 186.6 | Level : R+1 | ThisIsExisting | Existing
585668 | R+2 | Level: R+2 | 199.8 | Level : R+2 | ThisIsExisting | Existing
585669 | RDC | Level: RDC | 173.4 | Level : RDC | ThisIsExisting | Existing
585670 | RDC | Level: RDC | 1091.7 | Level : RDC | ThisIsExisting | Existing
585671 | RDC | Level: RDC | 2010 | Level : RDC | ThisIsExisting | Existing
585672 | RDC | Level: RDC | 2928.3 | Level : RDC | ThisIsExisting | Existing
585673 | R+1 | Level: R+1 | 3859.8 | Level : R+1 | ThisIsExisting | Existing
585674 | R+2 | Level: R+2 | 1118.1 | Level : R+2 | ThisIsExisting | Existing
585675 | R+1 | Level: R+1 | 4778.1 | Level : R+1 | ThisIsExisting | Existing
585676 | R+2 | Level: R+2 | 2036.4 | Level : R+2 | ThisIsExisting | Existing
585677 | R+1 | Level: R+1 | 5696.4 | Level : R+1 | ThisIsExisting | Existing
585678 | R+2 | Level: R+2 | 2954.7 | Level : R+2 | ThisIsExisting | Existing
585679 | R+1 | Level: R+1 | 6614.7 | Level : R+1 | ThisIsExisting | Existing
585741 | R+2 | Level: R+2 | 1118.1 | Level : R+2 | ThisIsExisting | Existing
585768 | R+2 | Level: R+2 | 199.8 | Level : R+2 | ThisIsExisting | Existing
585815 | TOITURE | Level: TOITURE | -565.3 | Level : TOITURE | ThisIsExisting | Existing
585816 | TOITURE | Level: TOITURE | -1483.6 | Level : TOITURE | ThisIsExisting | Existing
585858 | R+2 | Level: R+2 | 1118.1 | Level : R+2 | ThisIsExisting | Existing
585869 | R+2 | Level: R+2 | 2036.4 | Level : R+2 | ThisIsExisting | Existing
586359 | R+2 | Level: R+2 | 1118.1 | Level : R+2 | ThisIsNew | New Construction
586371 | R+2 | Level: R+2 | 2036.4 | Level : R+2 | ThisIsNew | New Construction
586385 | R+2 | Level: R+2 | 2954.7 | Level : R+2 | ThisIsNew | New Construction
586433 | R+2 | Level: R+2 | 2954.7 | Level : R+2 | ThisIsExisting | Existing

# IfcBeam: NBS_AndertonConcreteProductsLtd_PrcstConcPnls_BallastBoard300:PPT TYPE8 (2)
Type - Constraints - Default Elevation: 0 mm
Type - Data - EdgeDetails: Plain; EnvironmentalProductDeclaration: n/a; Weight: 60 kg
Type - Dimensions - Height: 2920 mm; Length: 1840 mm; Width: 430 mm
Type - General - Author: NBS; BIMObjectName: NBS_AndertonConcreteProductsLtd_PrecastConcretePanels_BallastBoard300; ManufacturerName: Anderton Concrete Products Ltd; NBSDescription: Precast concrete paels; Revision: n/a; Uniclass2015Code: Pr_20_93_71_17; Uniclass2015Title: Concrete panels; Uniclass2015Version: Products v1.5; Version: 4
Type - Identity Data - Type Name: PPT TYPE8
Type - Materials and Finishes - PanelMaterial: Concrete, Precast Smooth, Light Grey
Type - Other - Category: Generic Models; AccessibilityPerformance: n/a; AssetType: Fixed; CodePerformance: n/a; Color: n/a; Constituents: n/a; DurationUnit: year; ExpectedLife: n/a; Family Name: NBS_AndertonConcreteProductsLtd_PrcstConcPnls_BallastBoard300; Features: Quick and easy to install, contains steel reinforcement, Network Rail approved; Finish: n/a; Grade: n/a; Material: Concrete; ModelNumber: n/a; ModelReference: Ballast Board; Name: PrecastConcretePanels_BallastBoard300_AndertonConcreteProductsLtd; NominalHeight: 2910 mm; NominalLength: 10337 mm; NominalWidth: 200 mm; ReplacementCost: n/a; Shape: Rectangular; Size: 1830 x 300 x 50 mm; SustainabilityPerformance: n/a; WarrantyDescription: n/a; WarrantyDurationLabor: n/a; WarrantyDurationParts: n/a; WarrantyDurationUnit: year; WarrantyGuarantorLabor: n/a; WarrantyGuarantorParts: n/a
Type - Pset_BeamCommon - LoadBearing: yes; Reference: n/a; Slope: 0 deg; IsExternal: yes; Span: 1830 mm; FireRating: n/a
Type - Pset_ConcreteElementGeneral - EnvironmentalClass: n/a; FireRating: n/a; LifeCycleEnvironmentalLoad: n/a; DimensionalAccuracyClass: n/a; ConstructionToleranceClass: n/a; ConstructionType: n/a
Type - Pset_ElementShading - Color: n/a
Type - Pset_ManufacturerTypeInformation - ModelReference: Ballast Board
Type - Pset_ProductRequirements - Name: PrecastConcretePanels_BallastBoard300_AndertonConcreteProductsLtd; Category: Generic Models
Type - Pset_QuantityTakeOff - Reference: n/a
Type - Pset_ReinforcementBarPitchOfBeam - Reference: n/a
Material: Concrete, Precast Smooth, Light Grey
Pset_ManufacturerOccurrence - BarCode: n/a; SerialNumber: n/a
Pset_PrecastConcreteElementGeneral - SerialNumber: n/a
Pset_QuantityTakeOff - sets with these values: 2
Constraints - Moves With Nearby Elements: no
Dimensions - Area: 7.4196 m2; Volume: 2.3103 m3
Identity Data - Comments: ThisIsNew
Other - AssetIdentifier: n/a; BarCode: n/a; Family: NBS_AndertonConcreteProductsLtd_PrcstConcPnls_BallastBoard300: PPT TYPE8; Family and Type: NBS_AndertonConcreteProductsLtd_PrcstConcPnls_BallastBoard300: PPT TYPE8; InstallationDate: 1900-12-31T23:59:59; SerialNumber: n/a; TagNumber: n/a; Type: NBS_AndertonConcreteProductsLtd_PrcstConcPnls_BallastBoard300: PPT TYPE8; Type Id: NBS_AndertonConcreteProductsLtd_PrcstConcPnls_BallastBoard300: PPT TYPE8; WarrantyStartDate: 1900-12-31T23:59:59
Phasing - Phase Created: New Construction
Structural - Rebar Cover: Rebar Cover Settings: Rebar Cover 1
Name (NBS_AndertonConcreteProductsLtd_PrcstConcPnls_BallastBoard300:PPT TYPE8:...) | In | Level | Elevation from Level (mm) = Offset from Host (mm) | Host
504509 | R+1 | Level: R+1 | -740 | Level : R+1
504630 | R+2 | Level: R+2 | -1480 | Level : R+2

# IfcBuildingElementProxy: Panneaux fille 18 ajoures:Panneaux fille 18 ajoures (18)
Type - Material: Concrete, Precast Smooth, Light Grey
Type - Constraints - Default Elevation: 0 mm
Type - Dimensions - Height: 910 mm; Length: 4938 mm; Width: 205 mm
Type - Identity Data - Type Name: Panneaux fille 18 ajoures
Type - Other - Category: Generic Models; Family Name: Panneaux fille 18 ajoures
Type - Pset_BuildingElementProxyCommon - Reference: Panneaux fille 18 ajoures
Type - Pset_ProductRequirements - Category: Generic Models
Type - Pset_QuantityTakeOff - Reference: Panneaux fille 18 ajoures
Type - Pset_ProvisionForVoid - Width: 205 mm; Height: 910 mm
Pset_BuildingElementProxyCommon - sets with these values: 2
Constraints - Moves With Nearby Elements: no
Dimensions - Area: 4.34066 m2; Volume: 0.393579 m3
Identity Data - Comments: ThisIsNew
Other - Family: Panneaux fille 18 ajoures: Panneaux fille 18 ajoures; Family and Type: Panneaux fille 18 ajoures: Panneaux fille 18 ajoures; Type: Panneaux fille 18 ajoures: Panneaux fille 18 ajoures; Type Id: Panneaux fille 18 ajoures: Panneaux fille 18 ajoures
Phasing - Phase Created: New Construction
Name (Panneaux fille 18 ajoures:Panneaux fille 18 ajoures:...) | In | Level | Elevation from Level (mm) = Offset from Host (mm) | Host
513119 | RDC | Level: RDC | 2960 | Level : RDC
513120 | R+1 | Level: R+1 | 220 | Level : R+1
513121 | R+1 | Level: R+1 | 1140 | Level : R+1
513122 | R+1 | Level: R+1 | 2060 | Level : R+1
513123 | R+1 | Level: R+1 | 2980 | Level : R+1
513124 | R+1 | Level: R+1 | 3900 | Level : R+1
513125 | R+2 | Level: R+2 | 1160 | Level : R+2
517682 | R+2 | Level: R+2 | 2080 | Level : R+2
517698 | R+2 | Level: R+2 | 3000 | Level : R+2
575380 | RDC | Level: RDC | 2960 | Level : RDC
575381 | R+1 | Level: R+1 | 220 | Level : R+1
575382 | R+1 | Level: R+1 | 1140 | Level : R+1
575383 | R+1 | Level: R+1 | 2060 | Level : R+1
575384 | R+1 | Level: R+1 | 2980 | Level : R+1
575385 | R+1 | Level: R+1 | 3900 | Level : R+1
575386 | R+2 | Level: R+2 | 1160 | Level : R+2
575387 | R+2 | Level: R+2 | 2080 | Level : R+2
575388 | R+2 | Level: R+2 | 3000 | Level : R+2

# IfcBuildingElementProxy: Panneaux fille 18 les extremes:Panneaux fille 18 les extremes (24)
Type - Material: Concrete, Precast Smooth, Light Grey
Type - Constraints - Default Elevation: 0 mm
Type - Dimensions - Height: 910 mm; Length: 4938 mm; Width: 205 mm
Type - Identity Data - Type Name: Panneaux fille 18 les extremes
Type - Other - Category: Generic Models; Family Name: Panneaux fille 18 les extremes
Type - Pset_BuildingElementProxyCommon - Reference: Panneaux fille 18 les extremes
Type - Pset_ProductRequirements - Category: Generic Models
Type - Pset_QuantityTakeOff - Reference: Panneaux fille 18 les extremes
Type - Pset_ProvisionForVoid - Width: 205 mm; Height: 910 mm
Pset_BuildingElementProxyCommon - sets with these values: 2
Constraints - Moves With Nearby Elements: no
Dimensions - Area: 3.24546 m2; Volume: 0.370842 m3
Identity Data - Comments: ThisIsNew
Other - Family: Panneaux fille 18 les extremes: Panneaux fille 18 les extremes; Family and Type: Panneaux fille 18 les extremes: Panneaux fille 18 les extremes; Type: Panneaux fille 18 les extremes: Panneaux fille 18 les extremes; Type Id: Panneaux fille 18 les extremes: Panneaux fille 18 les extremes
Phasing - Phase Created: New Construction
Name (Panneaux fille 18 les extremes:Panneaux fille 18 les extremes:...) | In | Level | Elevation from Level (mm) = Offset from Host (mm) | Host
575469 | RDC | Level: RDC | 2960 | Level : RDC
575470 | R+1 | Level: R+1 | 220 | Level : R+1
575471 | R+1 | Level: R+1 | 1140 | Level : R+1
575472 | R+1 | Level: R+1 | 2060 | Level : R+1
575473 | R+1 | Level: R+1 | 2980 | Level : R+1
575474 | R+1 | Level: R+1 | 3900 | Level : R+1
575475 | R+2 | Level: R+2 | 1160 | Level : R+2
575476 | R+2 | Level: R+2 | 2080 | Level : R+2
575477 | R+2 | Level: R+2 | 3000 | Level : R+2
575478 | RDC | Level: RDC | 2040 | Level : RDC
575479 | RDC | Level: RDC | 1120 | Level : RDC
575480 | RDC | Level: RDC | 200 | Level : RDC
575492 | RDC | Level: RDC | 2960 | Level : RDC
575493 | R+1 | Level: R+1 | 220 | Level : R+1
575494 | R+1 | Level: R+1 | 1140 | Level : R+1
575495 | R+1 | Level: R+1 | 2060 | Level : R+1
575496 | R+1 | Level: R+1 | 2980 | Level : R+1
575497 | R+1 | Level: R+1 | 3900 | Level : R+1
575498 | R+2 | Level: R+2 | 1160 | Level : R+2
575499 | R+2 | Level: R+2 | 2080 | Level : R+2
575500 | R+2 | Level: R+2 | 3000 | Level : R+2
575501 | RDC | Level: RDC | 2040 | Level : RDC
575502 | RDC | Level: RDC | 1120 | Level : RDC
575503 | RDC | Level: RDC | 200 | Level : RDC

# IfcBuildingElementProxy: Panneaux fille 18:Panneaux fille 18 (138)
Type - Material: Concrete, Precast Smooth, Light Grey
Type - Constraints - Default Elevation: 0 mm
Type - Dimensions - Height: 910 mm; Length: 4938 mm; Width: 205 mm
Type - Identity Data - Type Name: Panneaux fille 18
Type - Other - Category: Generic Models; Family Name: Panneaux fille 18
Type - Pset_BuildingElementProxyCommon - Reference: Panneaux fille 18
Type - Pset_ProductRequirements - Category: Generic Models
Type - Pset_QuantityTakeOff - Reference: Panneaux fille 18
Type - Pset_ProvisionForVoid - Width: 205 mm; Height: 910 mm
Pset_BuildingElementProxyCommon - sets with these values: 2
Constraints - Moves With Nearby Elements: no
Dimensions - Area: 6.33921 m2; Volume: 0.741105 m3
Identity Data - Comments: ThisIsNew
Other - Family: Panneaux fille 18: Panneaux fille 18; Family and Type: Panneaux fille 18: Panneaux fille 18; Type: Panneaux fille 18: Panneaux fille 18; Type Id: Panneaux fille 18: Panneaux fille 18
Phasing - Phase Created: New Construction
Name (Panneaux fille 18:Panneaux fille 18:...) | In | Level | Elevation from Level (mm) = Offset from Host (mm) | Host
575138 | RDC | Level: RDC | 2960 | Level : RDC
575139 | R+1 | Level: R+1 | 220 | Level : R+1
575140 | R+1 | Level: R+1 | 1140 | Level : R+1
575141 | R+1 | Level: R+1 | 2060 | Level : R+1
575142 | R+1 | Level: R+1 | 2980 | Level : R+1
575143 | R+1 | Level: R+1 | 3900 | Level : R+1
575144 | R+2 | Level: R+2 | 1160 | Level : R+2
575145 | R+2 | Level: R+2 | 2080 | Level : R+2
575146 | R+2 | Level: R+2 | 3000 | Level : R+2
575190 | RDC | Level: RDC | 2960 | Level : RDC
575191 | R+1 | Level: R+1 | 220 | Level : R+1
575192 | R+1 | Level: R+1 | 1140 | Level : R+1
575193 | R+1 | Level: R+1 | 2060 | Level : R+1
575194 | R+1 | Level: R+1 | 2980 | Level : R+1
575195 | R+1 | Level: R+1 | 3900 | Level : R+1
575196 | R+2 | Level: R+2 | 1160 | Level : R+2
575197 | R+2 | Level: R+2 | 2080 | Level : R+2
575198 | R+2 | Level: R+2 | 3000 | Level : R+2
575199 | RDC | Level: RDC | 2040 | Level : RDC
575200 | RDC | Level: RDC | 1120 | Level : RDC
575201 | RDC | Level: RDC | 200 | Level : RDC
575226 | RDC | Level: RDC | 2960 | Level : RDC
575227 | R+1 | Level: R+1 | 220 | Level : R+1
575228 | R+1 | Level: R+1 | 1140 | Level : R+1
575229 | R+1 | Level: R+1 | 2060 | Level : R+1
575230 | R+1 | Level: R+1 | 2980 | Level : R+1
575231 | R+1 | Level: R+1 | 3900 | Level : R+1
575232 | R+2 | Level: R+2 | 1160 | Level : R+2
575233 | R+2 | Level: R+2 | 2080 | Level : R+2
575234 | R+2 | Level: R+2 | 3000 | Level : R+2
575235 | RDC | Level: RDC | 2040 | Level : RDC
575236 | RDC | Level: RDC | 1120 | Level : RDC
575237 | RDC | Level: RDC | 200 | Level : RDC
575242 | RDC | Level: RDC | 2960 | Level : RDC
575243 | R+1 | Level: R+1 | 220 | Level : R+1
575244 | R+1 | Level: R+1 | 1140 | Level : R+1
575245 | R+1 | Level: R+1 | 2060 | Level : R+1
575246 | R+1 | Level: R+1 | 2980 | Level : R+1
575247 | R+1 | Level: R+1 | 3900 | Level : R+1
575248 | R+2 | Level: R+2 | 1160 | Level : R+2
575249 | R+2 | Level: R+2 | 2080 | Level : R+2
575250 | R+2 | Level: R+2 | 3000 | Level : R+2
575251 | RDC | Level: RDC | 2040 | Level : RDC
575252 | RDC | Level: RDC | 1120 | Level : RDC
575253 | RDC | Level: RDC | 200 | Level : RDC
575258 | RDC | Level: RDC | 2960 | Level : RDC
575259 | R+1 | Level: R+1 | 220 | Level : R+1
575260 | R+1 | Level: R+1 | 1140 | Level : R+1
575261 | R+1 | Level: R+1 | 2060 | Level : R+1
575262 | R+1 | Level: R+1 | 2980 | Level : R+1
575263 | R+1 | Level: R+1 | 3900 | Level : R+1
575264 | R+2 | Level: R+2 | 1160 | Level : R+2
575265 | R+2 | Level: R+2 | 2080 | Level : R+2
575266 | R+2 | Level: R+2 | 3000 | Level : R+2
575267 | RDC | Level: RDC | 2040 | Level : RDC
575268 | RDC | Level: RDC | 1120 | Level : RDC
575269 | RDC | Level: RDC | 200 | Level : RDC
575274 | RDC | Level: RDC | 2960 | Level : RDC
575275 | R+1 | Level: R+1 | 220 | Level : R+1
575276 | R+1 | Level: R+1 | 1140 | Level : R+1
575277 | R+1 | Level: R+1 | 2060 | Level : R+1
575278 | R+1 | Level: R+1 | 2980 | Level : R+1
575279 | R+1 | Level: R+1 | 3900 | Level : R+1
575280 | R+2 | Level: R+2 | 1160 | Level : R+2
575281 | R+2 | Level: R+2 | 2080 | Level : R+2
575282 | R+2 | Level: R+2 | 3000 | Level : R+2
575283 | RDC | Level: RDC | 2040 | Level : RDC
575284 | RDC | Level: RDC | 1120 | Level : RDC
575285 | RDC | Level: RDC | 200 | Level : RDC
575290 | RDC | Level: RDC | 2960 | Level : RDC
575291 | R+1 | Level: R+1 | 220 | Level : R+1
575292 | R+1 | Level: R+1 | 1140 | Level : R+1
575293 | R+1 | Level: R+1 | 2060 | Level : R+1
575294 | R+1 | Level: R+1 | 2980 | Level : R+1
575295 | R+1 | Level: R+1 | 3900 | Level : R+1
575296 | R+2 | Level: R+2 | 1160 | Level : R+2
575297 | R+2 | Level: R+2 | 2080 | Level : R+2
575298 | R+2 | Level: R+2 | 3000 | Level : R+2
575303 | RDC | Level: RDC | 2960 | Level : RDC
575304 | R+1 | Level: R+1 | 220 | Level : R+1
575305 | R+1 | Level: R+1 | 1140 | Level : R+1
575306 | R+1 | Level: R+1 | 2060 | Level : R+1
575307 | R+1 | Level: R+1 | 2980 | Level : R+1
575308 | R+1 | Level: R+1 | 3900 | Level : R+1
575309 | R+2 | Level: R+2 | 1160 | Level : R+2
575310 | R+2 | Level: R+2 | 2080 | Level : R+2
575311 | R+2 | Level: R+2 | 3000 | Level : R+2
575312 | RDC | Level: RDC | 2040 | Level : RDC
575313 | RDC | Level: RDC | 1120 | Level : RDC
575314 | RDC | Level: RDC | 200 | Level : RDC
575316 | RDC | Level: RDC | 2960 | Level : RDC
575317 | R+1 | Level: R+1 | 220 | Level : R+1
575318 | R+1 | Level: R+1 | 1140 | Level : R+1
575319 | R+1 | Level: R+1 | 2060 | Level : R+1
575320 | R+1 | Level: R+1 | 2980 | Level : R+1
575321 | R+1 | Level: R+1 | 3900 | Level : R+1
575322 | R+2 | Level: R+2 | 1160 | Level : R+2
575323 | R+2 | Level: R+2 | 2080 | Level : R+2
575324 | R+2 | Level: R+2 | 3000 | Level : R+2
575325 | RDC | Level: RDC | 2040 | Level : RDC
575326 | RDC | Level: RDC | 1120 | Level : RDC
575327 | RDC | Level: RDC | 200 | Level : RDC
575329 | RDC | Level: RDC | 2960 | Level : RDC
575330 | R+1 | Level: R+1 | 220 | Level : R+1
575331 | R+1 | Level: R+1 | 1140 | Level : R+1
575332 | R+1 | Level: R+1 | 2060 | Level : R+1
575333 | R+1 | Level: R+1 | 2980 | Level : R+1
575334 | R+1 | Level: R+1 | 3900 | Level : R+1
575335 | R+2 | Level: R+2 | 1160 | Level : R+2
575336 | R+2 | Level: R+2 | 2080 | Level : R+2
575337 | R+2 | Level: R+2 | 3000 | Level : R+2
575338 | RDC | Level: RDC | 2040 | Level : RDC
575339 | RDC | Level: RDC | 1120 | Level : RDC
575340 | RDC | Level: RDC | 200 | Level : RDC
575342 | RDC | Level: RDC | 2960 | Level : RDC
575343 | R+1 | Level: R+1 | 220 | Level : R+1
575344 | R+1 | Level: R+1 | 1140 | Level : R+1
575345 | R+1 | Level: R+1 | 2060 | Level : R+1
575346 | R+1 | Level: R+1 | 2980 | Level : R+1
575347 | R+1 | Level: R+1 | 3900 | Level : R+1
575348 | R+2 | Level: R+2 | 1160 | Level : R+2
575349 | R+2 | Level: R+2 | 2080 | Level : R+2
575350 | R+2 | Level: R+2 | 3000 | Level : R+2
575351 | RDC | Level: RDC | 2040 | Level : RDC
575352 | RDC | Level: RDC | 1120 | Level : RDC
575353 | RDC | Level: RDC | 200 | Level : RDC
575355 | RDC | Level: RDC | 2960 | Level : RDC
575356 | R+1 | Level: R+1 | 220 | Level : R+1
575357 | R+1 | Level: R+1 | 1140 | Level : R+1
575358 | R+1 | Level: R+1 | 2060 | Level : R+1
575359 | R+1 | Level: R+1 | 2980 | Level : R+1
575360 | R+1 | Level: R+1 | 3900 | Level : R+1
575361 | R+2 | Level: R+2 | 1160 | Level : R+2
575362 | R+2 | Level: R+2 | 2080 | Level : R+2
575363 | R+2 | Level: R+2 | 3000 | Level : R+2
575364 | RDC | Level: RDC | 2040 | Level : RDC
575365 | RDC | Level: RDC | 1120 | Level : RDC
575366 | RDC | Level: RDC | 200 | Level : RDC

# IfcColumn: M_Precast-Rectangular Column:430X200 (2)
Type - PredefinedType: COLUMN; Material: Concrete - Precast Concrete - 35 MPa
Type - Dimensions - b: 430 mm; Chamfer: 25 mm; h: 200 mm
Type - Identity Data - OmniClass Number: 23.25.30.11.14.11; OmniClass Title: Columns; Type Name: 430X200
Type - Other - Category: Structural Columns; Family Name: M_Precast-Rectangular Column
Type - Structural - Section Shape: 0
Type - Pset_ColumnCommon - IsExternal: no; LoadBearing: yes; Reference: 430X200
Type - Pset_ProductRequirements - Category: Structural Columns
Type - Pset_QuantityTakeOff - Reference: 430X200
Type - Pset_ReinforcementBarPitchOfColumn - Reference: 430X200
Pset_QuantityTakeOff - sets with these values: 2
Constraints - Column Style: Vertical; Moves With Grids: yes; Room Bounding: yes
Materials and Finishes - Structural Material: Concrete - Precast Concrete - 35 MPa
Other - Family: M_Precast-Rectangular Column: 430X200; Family and Type: M_Precast-Rectangular Column: 430X200; Type: M_Precast-Rectangular Column: 430X200; Type Id: M_Precast-Rectangular Column: 430X200
Structural - Enable Analytical Model: yes; Rebar Cover - Bottom Face: Rebar Cover Settings: Rebar Cover 1; Rebar Cover - Other Faces: Rebar Cover Settings: Rebar Cover 1; Rebar Cover - Top Face: Rebar Cover Settings: Rebar Cover 1
Name (M_Precast-Rectangular Column:430X200:...) | In | Base Level = Level | Base Offset (mm) | Column Location Mark | Top Level | Top Offset (mm) | Length (mm) | Volume (m3) | Phase Created
417607 | R+1 | Level: R+1 | -750 | A1-1(115.0) | Level: R+2 | -1500 | 2910 | 0.246622 | New Construction | Identity Data - Comments: ThisIsNew
492508 | R-1 | Level: R-1 | -2 | A1-1 | Level: RDC | 0 | 3502 | 0.296795 | Existing

# IfcColumn: M_Precast-Rectangular Column:430X200 (2)
Type - PredefinedType: COLUMN; Material: Concrete, Precast Smooth, Light Grey
Type - Dimensions - b: 430 mm; Chamfer: 25 mm; h: 200 mm
Type - Identity Data - OmniClass Number: 23.25.30.11.14.11; OmniClass Title: Columns; Type Name: 430X200
Type - Other - Category: Structural Columns; Family Name: M_Precast-Rectangular Column
Type - Structural - Section Shape: 0
Type - Pset_ColumnCommon - IsExternal: no; LoadBearing: yes; Reference: 430X200
Type - Pset_ProductRequirements - Category: Structural Columns
Type - Pset_QuantityTakeOff - Reference: 430X200
Type - Pset_ReinforcementBarPitchOfColumn - Reference: 430X200
Pset_QuantityTakeOff - sets with these values: 2
Constraints - Column Style: Vertical; Moves With Grids: yes; Room Bounding: yes
Identity Data - Comments: ThisIsNew
Materials and Finishes - Structural Material: Concrete, Precast Smooth, Light Grey
Other - Family: M_Precast-Rectangular Column: 430X200; Family and Type: M_Precast-Rectangular Column: 430X200; Type: M_Precast-Rectangular Column: 430X200; Type Id: M_Precast-Rectangular Column: 430X200
Phasing - Phase Created: New Construction
Structural - Enable Analytical Model: yes; Rebar Cover - Bottom Face: Rebar Cover Settings: Rebar Cover 1; Rebar Cover - Other Faces: Rebar Cover Settings: Rebar Cover 1; Rebar Cover - Top Face: Rebar Cover Settings: Rebar Cover 1
Name (M_Precast-Rectangular Column:430X200:...) | In | Base Level = Level | Base Offset (mm) | Column Location Mark | Top Level | Top Offset (mm) | Length (mm) | Volume (m3)
400652 | RDC | Level: RDC | 0 | A1-1(110.0) | Level: R+1 | -750 | 2910 | 0.246622
417745 | R+2 | Level: R+2 | -1500 | A1-1(105.0) | Level: TOP | 0 | 5410 | 0.458498

# IfcColumn: M_Precast-Square Column:430x430 (5)
Type - PredefinedType: COLUMN; Material: Concrete, Precast Smooth, Light Grey
Type - Dimensions - b: 430 mm; Chamfer: 0 mm
Type - Identity Data - OmniClass Number: 23.25.30.11.14.11; OmniClass Title: Columns; Type Name: 430x430
Type - Other - Category: Structural Columns; Family Name: M_Precast-Square Column; TransChamfer: 2 mm
Type - Structural - Section Shape: 0
Type - Pset_ColumnCommon - Reference: 430x430; IsExternal: no; LoadBearing: yes
Type - Pset_ProductRequirements - Category: Structural Columns
Type - Pset_QuantityTakeOff - Reference: 430x430
Type - Pset_ReinforcementBarPitchOfColumn - Reference: 430x430
Pset_QuantityTakeOff - sets with these values: 2
Constraints - Column Style: Vertical; Moves With Grids: yes; Room Bounding: yes
Identity Data - Comments: ThisIsExisting
Materials and Finishes - Structural Material: Concrete, Precast Smooth, Light Grey
Other - Family: M_Precast-Square Column: 430x430; Family and Type: M_Precast-Square Column: 430x430; Rebar Grids W: 0.98 kN; Single Rebar W: 0.49 kN; Tie Rod W: 0.294 kN; Type: M_Precast-Square Column: 430x430; Type Id: M_Precast-Square Column: 430x430
Phasing - Phase Created: Existing
Structural - Enable Analytical Model: yes; Rebar Cover - Bottom Face: Rebar Cover Settings: Rebar Cover 1; Rebar Cover - Other Faces: Rebar Cover Settings: Rebar Cover 1; Rebar Cover - Top Face: Rebar Cover Settings: Rebar Cover 1; Rebar Grids Weight: 100; Single Rebar Weight: 50; Tie Rod Weight: 30
Name (M_Precast-Square Column:430x430:...) | In | Base Level = Level | Base Offset (mm) | Column Location Mark | Top Level | Top Offset (mm) | Length (mm) | Volume (m3)
382164 | R-1 | Level: R-1 | -300 | A-0 | Level: RDC | 0 | 3800 | 0.70262 | Constraints - Top is Attached: yes; Construction - Attachment Justification At Top: Minimum Intersection; Offset From Attachment At Top: 0 mm
382166 | R-1 | Level: R-1 | -300 | A1-0 | Level: RDC | 0 | 3800 | 0.70262 | Constraints - Top is Attached: yes; Construction - Attachment Justification At Top: Minimum Intersection; Offset From Attachment At Top: 0 mm
400654 | RDC | Level: RDC | 0 | A1-0 | Level: R+1 | -750 | 2910 | 0.538059
417609 | R+1 | Level: R+1 | -750 | A1-0 | Level: R+2 | -1500 | 2910 | 0.538059
417747 | R+2 | Level: R+2 | -1500 | A1-0 | Level: TOITURE | -2050 | 2970 | 0.549153

# IfcRailing: Railing:1100mm, Railing:1100mm:496270
In: R-1
Top Rail(Type) - Type: Top Rail Type: 50x50mm_Rectangular; Use Top Rail: yes; Height: 1100 mm
Other(Type) - Category: Railings; Family Name: Railing
Identity Data(Type) - Type Name: 1100mm
Construction(Type) - Angled Joins: No Connector; Baluster Offset: 0 mm; Landing Height Adjustment: 0 mm; Tangent Joins: Extend Rails to Meet; Use Landing Height Adjustment: no; Rail Connections: Trim; Railing Height: 1100 mm
Pset_ProductRequirements - Category: Railings
Pset_QuantityTakeOff - Reference: 1100mm
Pset_RailingCommon - IsExternal: no; Reference: 1100mm; Height: 1100 mm
Constraints - Base Offset: 0 mm; Offset from Path: 25.4 mm
Dimensions - Length: 5686.47 mm
Other - Category: Railings; Family: Railing: 1100mm; Family and Type: Railing: 1100mm; Type: Railing: 1100mm; Type Id: Railing: 1100mm
Phasing - Phase Created: New Construction

# IfcRailing: Railing:900mm_Pipe, Railing:900mm_Pipe:491088
In: RDC
Top Rail(Type) - Height: 900 mm; Type: Top Rail Type: 50x50mm_Rectangular; Use Top Rail: yes
Other(Type) - Category: Railings; Family Name: Railing
Identity Data(Type) - Type Name: 900mm_Pipe
Construction(Type) - Angled Joins: No Connector; Baluster Offset: 0 mm; Landing Height Adjustment: 0 mm; Rail Connections: Weld; Railing Height: 900 mm; Tangent Joins: Extend Rails to Meet; Use Landing Height Adjustment: no
Pset_ProductRequirements - Category: Railings
Pset_QuantityTakeOff - Reference: 900mm_Pipe
Pset_RailingCommon - IsExternal: no; Reference: 900mm_Pipe; Height: 900 mm
Constraints - Base Offset: 0 mm; Offset from Path: 25.4 mm
Dimensions - Length: 10039 mm
Other - Category: Railings; Family: Railing: 900mm_Pipe; Family and Type: Railing: 900mm_Pipe; Type: Railing: 900mm_Pipe; Type Id: Railing: 900mm_Pipe
Phasing - Phase Created: New Construction

# IfcSlab: Floor:Plancher S/SOL Fille 0-1, Floor:Plancher S/SOL Fille 0-1:493007
In: RDC
Type - PredefinedType: FLOOR; Material: Concrete, Cast-in-Place - C15 300 mm
Type - Analytical Properties - Roughness: 3; Absorptance: 0.7; Heat Transfer Coefficient (U): 3.48667; Thermal Mass: 42.1157; Thermal Resistance (R): 0.286807
Type - Construction - Function: Interior; Default Thickness: 300 mm
Type - Graphics - Coarse Scale Fill Color: 0
Type - Identity Data - Type Name: Plancher S/SOL Fille 0-1
Type - Materials and Finishes - Structural Material: Concrete, Cast-in-Place - C15
Type - Other - Category: Floors; Family Name: Floor
Type - Pset_ElementShading - Roughness: 914.4 mm
Type - Pset_ProductRequirements - Category: Floors
Type - Pset_QuantityTakeOff - Reference: Plancher S/SOL Fille 0-1
Type - Pset_ReinforcementBarPitchOfSlab - Reference: Plancher S/SOL Fille 0-1
Type - Pset_SlabCommon - IsExternal: no; Reference: Plancher S/SOL Fille 0-1; ThermalTransmittance: 3.48667 kg/K/s3
Pset_QuantityTakeOff - sets with these values: 2
Pset_SlabCommon - LoadBearing: yes; PitchAngle: 0 deg
Constraints - Room Bounding: yes; Level: Level: RDC; Related to Mass: no; Height Offset From Level: -800 mm
Dimensions - Area: 2.7778 m2; Core Thickness: 300 mm; Elevation at Bottom: -1100 mm; Elevation at Bottom Core: -1100 mm; Elevation at Bottom Survey: -1100 mm; Elevation at Top: -800 mm; Elevation at Top Core: -800 mm; Elevation at Top Survey: -800 mm; Perimeter: 6670 mm; Thickness: 300 mm; Volume: 0.83334 m3
Identity Data - Comments: ThisIsNew
Other - ElementID: 493007; Family: Floor: Plancher S/SOL Fille 0-1; Family and Type: Floor: Plancher S/SOL Fille 0-1; Type: Floor: Plancher S/SOL Fille 0-1; Type Id: Floor: Plancher S/SOL Fille 0-1
Phasing - Phase Created: New Construction
Structural - Enable Analytical Model: yes; Rebar Cover - Bottom Face: Rebar Cover Settings: Rebar Cover 1; Rebar Cover - Other Faces: Rebar Cover Settings: Rebar Cover 1; Rebar Cover - Top Face: Rebar Cover Settings: Rebar Cover 1; Structural: yes

# IfcSlab: Floor:Plancher S/SOL Fille 0-1 140mm (2)
In: RDC
Type - PredefinedType: FLOOR; Material: Concrete, Cast-in-Place - C15 140 mm
Type - Analytical Properties - Roughness: 3; Absorptance: 0.7; Heat Transfer Coefficient (U): 7.47143; Thermal Mass: 19.654; Thermal Resistance (R): 0.133843
Type - Construction - Function: Interior; Default Thickness: 140 mm
Type - Graphics - Coarse Scale Fill Color: 0
Type - Identity Data - Type Name: Plancher S/SOL Fille 0-1 140mm
Type - Materials and Finishes - Structural Material: Concrete, Cast-in-Place - C15
Type - Other - Category: Floors; Family Name: Floor
Type - Pset_ElementShading - Roughness: 914.4 mm
Type - Pset_ProductRequirements - Category: Floors
Type - Pset_QuantityTakeOff - Reference: Plancher S/SOL Fille 0-1 140mm
Type - Pset_ReinforcementBarPitchOfSlab - Reference: Plancher S/SOL Fille 0-1 140mm
Type - Pset_SlabCommon - IsExternal: no; Reference: Plancher S/SOL Fille 0-1 140mm; ThermalTransmittance: 7.47143 kg/K/s3
Pset_QuantityTakeOff - sets with these values: 2
Pset_SlabCommon - PitchAngle: 0 deg; LoadBearing: no
Constraints - Room Bounding: yes; Level: Level: RDC; Related to Mass: no; Height Offset From Level: -1030 mm
Dimensions - Area: 3.0228 m2; Elevation at Bottom: -1170 mm; Elevation at Top: -1030 mm; Perimeter: 6964 mm; Thickness: 140 mm; Volume: 0.423192 m3
Other - Family: Floor: Plancher S/SOL Fille 0-1 140mm; Family and Type: Floor: Plancher S/SOL Fille 0-1 140mm; Type: Floor: Plancher S/SOL Fille 0-1 140mm; Type Id: Floor: Plancher S/SOL Fille 0-1 140mm
Structural - Enable Analytical Model: no; Structural: no
Name (Floor:Plancher S/SOL Fille 0-1 140mm:...) | ElementID | Phase Created
496856 | 496856 | New Construction
498159 | 498159 | Existing

# IfcSlab: Monolithic Landing:200mm_Thickness (2)
Type - PredefinedType: LANDING
Type - Construction - Monolithic Thickness: 200 mm
Type - Identity Data - Type Name: 200mm_Thickness
Type - Materials and Finishes - Monolithic Material: Concrete, Cast-in-Place gray
Type - Other - Category: Landings; Family Name: Monolithic Landing
Type - Treads - Same as Run: yes
Type - Pset_ProductRequirements - Category: Landings
Type - Pset_QuantityTakeOff - Reference: 200mm_Thickness
Type - Pset_ReinforcementBarPitchOfSlab - Reference: 200mm_Thickness
Type - Pset_SlabCommon - IsExternal: no; Reference: 200mm_Thickness
Material: Concrete, Cast-in-Place gray
Pset_QuantityTakeOff - sets with these values: 2
Pset_SlabCommon - PitchAngle: 0 deg
Dimensions - Total Thickness: 201 mm
Other - Family: Monolithic Landing: 200mm_Thickness; Family and Type: Monolithic Landing: 200mm_Thickness; Type: Monolithic Landing: 200mm_Thickness; Type Id: Monolithic Landing: 200mm_Thickness
Phasing - Phase Created: New Construction
Name (Precast Stair:Stair:...) | In | Relative Height (mm)
490853 Landing 1 | RDC | 2702.41
496050 Landing 1 | R-1 | 1307.65

# IfcStair: Precast Stair:Precast_Stair (2)
ShapeType: TWO_STRAIGHT_RUN_STAIR
Pset_ProductRequirements - Category: Stairs
Pset_QuantityTakeOff - Reference: Precast_Stair
Pset_StairCommon - IsExternal: no; Reference: Precast_Stair; TreadLength: 250 mm
Dimensions - Actual Tread Depth: 250 mm; Tread/Riser Start Number: 1
Other - Category: Stairs; Family: Precast Stair: Precast_Stair; Family and Type: Precast Stair: Precast_Stair; Type: Precast Stair: Precast_Stair; Type Id: Precast Stair: Precast_Stair
Phasing - Phase Created: New Construction
Structural - Rebar Cover: Rebar Cover Settings: Rebar Cover 1
Supports(Type) - Left Lateral Offset: 0 mm; Middle Support: no; Middle Support Number: 0; Right Lateral Offset: 0 mm
Other(Type) - Category: Stairs; Family Name: Precast Stair
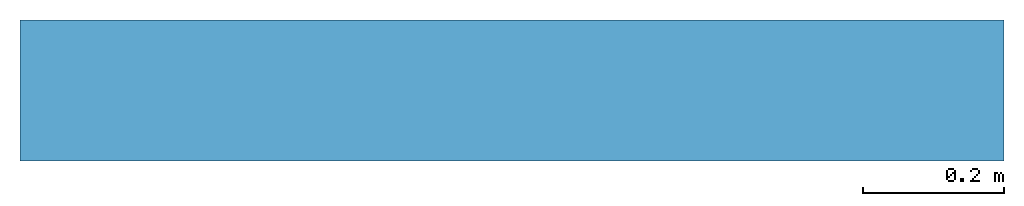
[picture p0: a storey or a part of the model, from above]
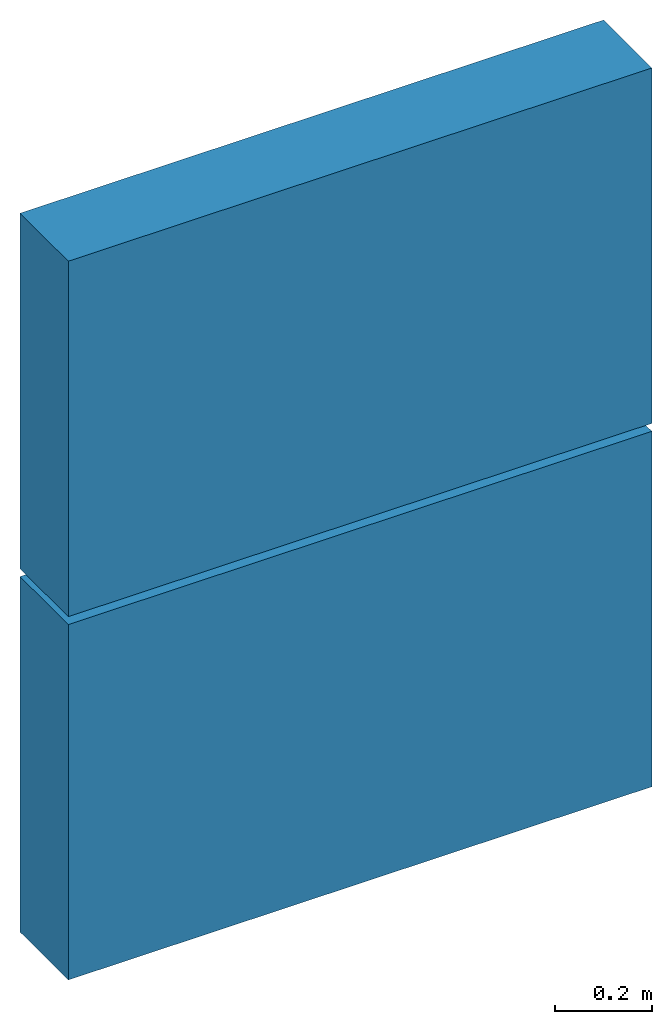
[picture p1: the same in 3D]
Properties of the parts of a building model (IFC2X3), part 2 of 2

# IfcStair: Precast Stair:Precast_Stair (2)
Calculation Rules(Type) - Maximum Riser Height: 170 mm; Minimum Run Width: 1000 mm; Minimum Tread Depth: 250 mm
Construction(Type) - Function: Interior; Landing Type: Monolithic Landing: 200mm_Thickness; Run Type: Monolithic Run: 1mm_Tread-175mm_Depth
End Connection(Type) - Connection Method: Notch; Horizontal Gap Distance: 10 mm; Notch Extension: 100 mm; Notch Thickness: 100 mm; Vertical Gap Distance: 10 mm
Graphics(Type) - Cut Mark Type: Stair Cut Mark: Sgl Zigzag
Identity Data(Type) - Type Name: Precast_Stair
Name (Precast Stair:Stair:...) | In | NumberOfRiser = NumberOfTreads = Actual Number of Risers | RiserHeight (mm) = Actual Riser Height (mm) | Base Level | Base Offset (mm) | Desired Stair Height (mm) | Top Level | Top Offset (mm) | Desired Number of Risers | ElementID
490853 | RDC | 28 | 158.966 | Level: RDC | -800 | 4610 | Level: R+1 | 150 | 29 | 490853
496050 | R-1 | 17 | 145.294 | Level: R-1 | 0 | 2470 | Level: RDC | -1030 | 17 | 496050

# IfcStairFlight: Monolithic Run:1mm_Tread-175mm_Depth (4)
Type - PredefinedType: STRAIGHT
Type - Construction - Structural Depth: 175 mm; Underside Surface: Smooth
Type - Identity Data - Type Name: 1mm_Tread-175mm_Depth
Type - Materials and Finishes - Monolithic Material: Concrete, Cast-in-Place gray; Riser Material: Concrete, Cast-in-Place gray; Tread Material: Concrete, Cast-in-Place gray
Type - Other - Category: Runs; Family Name: Monolithic Run
Type - Risers - Riser: no; Riser Thickness: 0 mm; Riser To Tread Connection: Extend Riser Behind Tread; Slanted: no
Type - Treads - Apply Nosing Profile: Front Only; Nosing Length: 0 mm; Tread: yes; Tread Thickness: 1 mm
Type - Pset_ProductRequirements - Category: Runs
Type - Pset_QuantityTakeOff - Reference: 1mm_Tread-175mm_Depth
Type - Pset_StairFlightCommon - Reference: 1mm_Tread-175mm_Depth; NosingLength: 0 mm
TreadLength: 0.82021 mm; Material: Concrete, Cast-in-Place gray
Pset_StairFlightCommon - TreadLength: 250 mm; TreadLengthAtOffset: 250 mm; TreadLengthAtInnerSide: 250 mm
Constraints - Location Line: Run: Center
Construction - Begin with Riser: yes; End with Riser: no
Dimensions - Actual Tread Depth: 250 mm
Other - Family: Monolithic Run: 1mm_Tread-175mm_Depth; Family and Type: Monolithic Run: 1mm_Tread-175mm_Depth; Type: Monolithic Run: 1mm_Tread-175mm_Depth; Type Id: Monolithic Run: 1mm_Tread-175mm_Depth
Phasing - Phase Created: New Construction
Name (Precast Stair:Stair:...) | In | NumberOfRiser = NumberOfTreads = Pset_StairFlightCommon, NumberOfRiser = Pset_StairFlightCommon, NumberOfTreads = Actual Number of Risers = Actual Number of Treads | RiserHeight (mm) | Pset_StairFlightCommon, RiserHeight (mm) = Actual Riser Height (mm) | WalkingLineOffset (mm) | Relative Base Height (mm) | Relative Top Height (mm) | Run Height (mm) | Actual Run Width (mm)
490853 Run 1 | RDC | 17 | 0.52154 | 158.966 | 2.64928 | 0 | 2702.41 | 2702.41 | 1615 | Construction - Extend Below Riser Base: 0 mm
490853 Run 2 | RDC | 11 | 0.52154 | 158.966 | 2.64928 | 2702.41 | 4451.03 | 1748.62 | 1615
496050 Run 1 | R-1 | 9 | 0.476687 | 145.294 | 2.70669 | 0 | 1307.65 | 1307.65 | 1650 | Construction - Extend Below Riser Base: 0 mm
496050 Run 2 | R-1 | 8 | 0.476687 | 145.294 | 2.70669 | 1307.65 | 2470 | 1162.35 | 1650

# IfcWallStandardCase: Basic Wall:Mur S/SOL 20 (3)
Type - PredefinedType: STANDARD; Material: Concrete - Cast-in-Place Concrete 200 mm
Type - Analytical Properties - Absorptance: 0.7; Roughness: 3
Type - Construction - Function: Exterior; Width: 200 mm; Wrapping at Inserts: Both
Type - Graphics - Coarse Scale Fill Color: 12632256; Coarse Scale Fill Pattern: <Solid fill>
Type - Identity Data - Keynote: F10; Type Name: Mur S/SOL 20
Type - Materials and Finishes - Structural Material: Concrete - Cast-in-Place Concrete
Type - Other - Category: Walls; Family Name: Basic Wall
Type - Pset_ElementShading - Roughness: 914.4 mm
Type - Pset_ProductRequirements - Category: Walls
Type - Pset_QuantityTakeOff - Reference: Mur S/SOL 20
Type - Pset_ReinforcementBarPitchOfWall - Reference: Mur S/SOL 20
Type - Pset_WallCommon - IsExternal: no; Reference: Mur S/SOL 20
Constraints - Room Bounding: yes; Top Offset: 0 mm; Base Offset: 0 mm; Base Extension Distance: 0 mm; Base is Attached: no; Cross-Section: Vertical; Location Line: Finish Face: Exterior; Related to Mass: no; Top Extension Distance: 0 mm; Top is Attached: no
Other - Family: Basic Wall: Mur S/SOL 20; Family and Type: Basic Wall: Mur S/SOL 20; Type: Basic Wall: Mur S/SOL 20; Type Id: Basic Wall: Mur S/SOL 20
Phasing - Phase Created: Existing
Pset_QuantityTakeOff - sets with these values: 2
Pset_WallCommon - IsExternal: yes; ExtendToStructure: no
Name (Basic Wall:Mur S/SOL 20:...) | In | Base Constraint | Unconnected Height (mm) | Area (m2) | Length (mm) | Volume (m3) | ElementID | Enable Analytical Model = Structural = LoadBearing | Rebar Cover - Other Faces = Rebar Cover - Exterior Face = Rebar Cover - Interior Face | Structural Usage
492767 | R-1 | Level: R-1 | 2000 | 3.3 | 1840 | 0.66 | 492767 | yes | Rebar Cover Settings: Rebar Cover 1 | Bearing
492980 | R-1 | Level: R-1 | 2000 | 3.3 | 1840 | 0.66 | 492980 | yes | Rebar Cover Settings: Rebar Cover 1 | Bearing
548321 | R+2 | Level: R+2 | 3520 | 4.94208 | 1404 | 0.988416 |  | no |  | Non-bearing | Constraints - Top Constraint: Level: TOITURE; Identity Data - Comments: ThisIsExisting

# IfcWallStandardCase: Basic Wall:Mur S/SOL 21, Basic Wall:Mur S/SOL 21:494140
In: R-1
Type - PredefinedType: STANDARD; Material: Concrete - Cast-in-Place Concrete 210 mm
Type - Analytical Properties - Roughness: 3; Absorptance: 0.7
Type - Construction - Function: Exterior; Wrapping at Inserts: Both; Width: 210 mm
Type - Graphics - Coarse Scale Fill Pattern: <Solid fill>; Coarse Scale Fill Color: 12632256
Type - Identity Data - Keynote: F10; Type Name: Mur S/SOL 21
Type - Materials and Finishes - Structural Material: Concrete - Cast-in-Place Concrete
Type - Other - Category: Walls; Family Name: Basic Wall
Type - Pset_ElementShading - Roughness: 914.4 mm
Type - Pset_ProductRequirements - Category: Walls
Type - Pset_QuantityTakeOff - Reference: Mur S/SOL 21
Type - Pset_ReinforcementBarPitchOfWall - Reference: Mur S/SOL 21
Type - Pset_WallCommon - IsExternal: no; Reference: Mur S/SOL 21
Constraints - Room Bounding: yes; Base Offset: 0 mm; Base Constraint: Level: R-1; Base Extension Distance: 0 mm; Base is Attached: no; Cross-Section: Vertical; Location Line: Finish Face: Exterior; Related to Mass: no; Top Extension Distance: 0 mm; Top is Attached: no; Top Constraint: Level: RDC; Top Offset: -800 mm; Unconnected Height: 2700 mm
Dimensions - Area: 3.7854 m2; Length: 1402 mm; Volume: 0.794934 m3
Other - ElementID: 494140; Family: Basic Wall: Mur S/SOL 21; Family and Type: Basic Wall: Mur S/SOL 21; Type: Basic Wall: Mur S/SOL 21; Type Id: Basic Wall: Mur S/SOL 21
Phasing - Phase Created: Existing
Structural - Enable Analytical Model: yes; Rebar Cover - Other Faces: Rebar Cover Settings: Rebar Cover 1; Rebar Cover - Exterior Face: Rebar Cover Settings: Rebar Cover 1; Rebar Cover - Interior Face: Rebar Cover Settings: Rebar Cover 1; Structural: yes; Structural Usage: Bearing
Pset_QuantityTakeOff - sets with these values: 2
Pset_WallCommon - LoadBearing: yes; IsExternal: yes; ExtendToStructure: no
